VERSION 5.8 ;
BUSBITCHARS "<>" ;
DIVIDERCHAR "/" ;

UNITS
   DATABASE MICRONS 1000 ;
END UNITS

LAYER M1
   TYPE ROUTING ;
   DIRECTION HORIZONTAL ;
   WIDTH 0.2 ;
   PITCH 0.4 ;
   ANTENNAMODEL OXIDE1 ;
      ANTENNAAREARATIO 100 ;
      ANTENNADIFFAREARATIO PWL ( ( 0.1 1.0 ) ( 0.2 1.5 ) ) ;
      ANTENNASIDEAREARATIO 50 ;
END M1

LAYER V1
   TYPE CUT ;
   WIDTH 0.15 ;
   ANTENNAMODEL OXIDE1 ;
      ANTENNAAREARATIO 80 ;
END V1

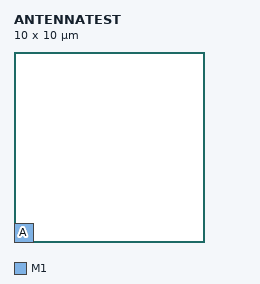
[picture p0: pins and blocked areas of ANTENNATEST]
MACRO ANTENNATEST
   CLASS CORE ;
   ORIGIN 0 0 ;
   SIZE 10 BY 10 ;

   PIN A
      DIRECTION INPUT ;
      ANTENNAPARTIALMETALAREA 1.5 LAYER M1 ;
      ANTENNAMODEL OXIDE1 ;
         ANTENNAGATEAREA 2.0 LAYER M1 ;
      PORT
         LAYER M1 ;
            RECT 0 0 1 1 ;
      END
   END A
END ANTENNATEST
